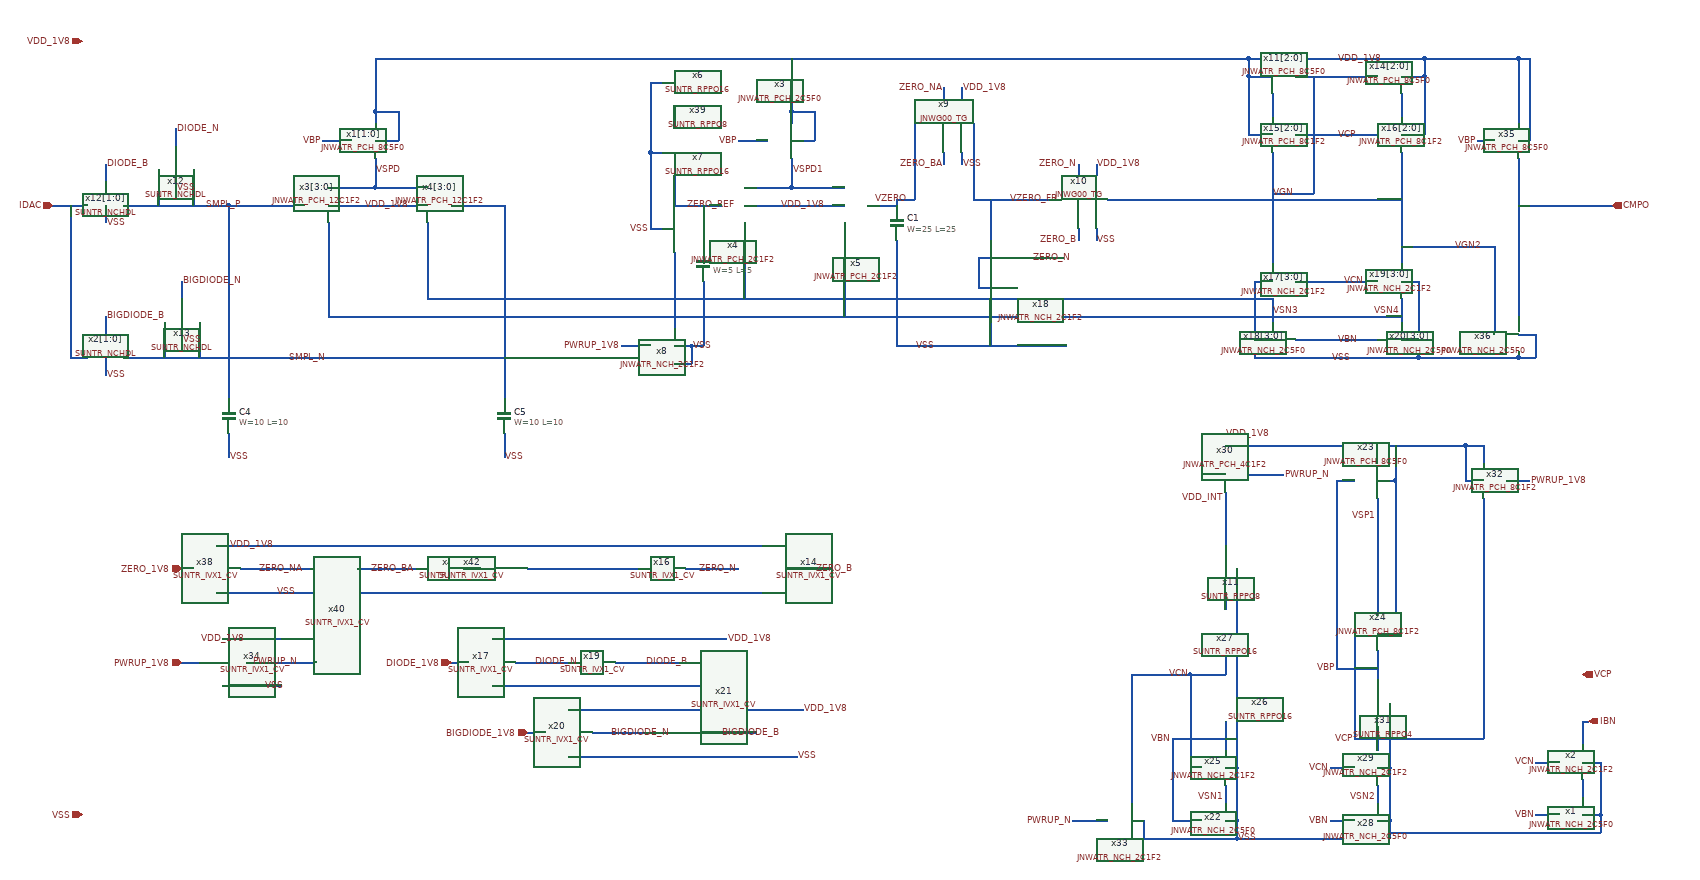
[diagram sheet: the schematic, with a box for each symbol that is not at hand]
v {xschem version=3.4.5 file_version=1.2
}
G {}
K {}
V {}
S {}
E {}
N 2170 -1300 2210 -1300 {
lab=VDD_1V8}
N 2170 -1330 2170 -1300 {
lab=VDD_1V8}
N 2170 -1330 2210 -1330 {
lab=VDD_1V8}
N 2210 -1330 2430 -1330 {
lab=VDD_1V8}
N 2430 -1300 2470 -1300 {
lab=VDD_1V8}
N 2470 -1330 2470 -1300 {
lab=VDD_1V8}
N 2430 -1330 2470 -1330 {
lab=VDD_1V8}
N 2430 -1270 2430 -1230 {
lab=#net1}
N 2210 -1270 2210 -1230 {
lab=#net2}
N 2170 -1200 2210 -1200 {
lab=VDD_1V8}
N 2170 -1300 2170 -1200 {
lab=VDD_1V8}
N 2430 -1200 2470 -1200 {
lab=VDD_1V8}
N 2470 -1300 2470 -1200 {
lab=VDD_1V8}
N 2210 -920 2210 -880 {
lab=VSN3}
N 2180 -950 2210 -950 {
lab=VSS}
N 2180 -950 2180 -820 {
lab=VSS}
N 2180 -820 2210 -820 {
lab=VSS}
N 2180 -850 2210 -850 {
lab=VSS}
N 2430 -920 2430 -880 {
lab=VSN4}
N 2430 -950 2460 -950 {
lab=VSS}
N 2460 -950 2460 -820 {
lab=VSS}
N 2430 -820 2460 -820 {
lab=VSS}
N 2430 -850 2460 -850 {
lab=VSS}
N 2210 -1170 2210 -980 {
lab=VGN}
N 2210 -820 2430 -820 {
lab=VSS}
N 2250 -850 2290 -850 {
lab=VBN}
N 2250 -950 2390 -950 {
lab=VCN}
N 2250 -1200 2390 -1200 {
lab=VCP}
N 2250 -1300 2390 -1300 {
lab=VGN}
N 2130 -90 2130 -60 {
lab=VSN1}
N 2130 -30 2150 -30 {
lab=VSS}
N 2150 -30 2150 0 {
lab=VSS}
N 2130 0 2150 0 {
lab=VSS}
N 2150 -120 2150 -30 {
lab=VSS}
N 2130 -120 2150 -120 {
lab=VSS}
N 2130 -200 2130 -150 {
lab=VBN}
N 2040 -30 2090 -30 {
lab=VBN}
N 2040 -170 2040 -30 {
lab=VBN}
N 2040 -170 2130 -170 {
lab=VBN}
N 2070 -120 2090 -120 {
lab=VCN}
N 2070 -280 2070 -120 {
lab=VCN}
N 2070 -280 2130 -280 {
lab=VCN}
N 2150 -240 2150 -120 {
lab=VSS}
N 2150 -350 2150 -240 {
lab=VSS}
N 2130 -310 2130 -280 {
lab=VCN}
N 2090 -620 2130 -620 {
lab=VDD_1V8}
N 2090 -650 2090 -620 {
lab=VDD_1V8}
N 2090 -650 2130 -650 {
lab=VDD_1V8}
N 2130 -690 2130 -650 {
lab=VDD_1V8}
N 2170 -620 2230 -620 {
lab=PWRUP_N}
N 2390 -90 2390 -60 {
lab=VSN2}
N 2390 -120 2410 -120 {
lab=VSS}
N 2410 -120 2410 -30 {
lab=VSS}
N 2390 -30 2410 -30 {
lab=VSS}
N 2390 0 2410 0 {
lab=VSS}
N 2410 -30 2410 0 {
lab=VSS}
N 2310 -120 2350 -120 {
lab=VCN}
N 2310 -30 2350 -30 {
lab=VBN}
N 2410 -230 2410 -120 {
lab=VSS}
N 2390 -190 2390 -150 {
lab=VCP}
N 2390 -320 2390 -270 {
lab=VBP}
N 2390 -350 2420 -350 {
lab=VDD_1V8}
N 2420 -450 2420 -350 {
lab=VDD_1V8}
N 2390 -610 2420 -610 {
lab=VDD_1V8}
N 2420 -640 2420 -610 {
lab=VDD_1V8}
N 2390 -580 2390 -540 {
lab=VSP1}
N 2350 -350 2350 -170 {
lab=VCP}
N 2350 -170 2390 -170 {
lab=VCP}
N 2320 -290 2390 -290 {
lab=VBP}
N 2320 -450 2320 -290 {
lab=VBP}
N 2320 -610 2350 -610 {
lab=VBP}
N 2130 -670 2390 -670 {
lab=VDD_1V8}
N 2390 -670 2390 -640 {
lab=VDD_1V8}
N 2570 -430 2570 -170 {
lab=VCP}
N 2390 -170 2570 -170 {
lab=VCP}
N 2540 -610 2570 -610 {
lab=VDD_1V8}
N 2540 -670 2540 -610 {
lab=VDD_1V8}
N 2540 -670 2570 -670 {
lab=VDD_1V8}
N 2570 -670 2570 -640 {
lab=VDD_1V8}
N 2390 -670 2540 -670 {
lab=VDD_1V8}
N 2610 -610 2650 -610 {
lab=PWRUP_1V8}
N 1970 0 2130 0 {
lab=VSS}
N 1970 -30 1990 -30 {
lab=VSS}
N 1990 -30 1990 0 {
lab=VSS}
N 1970 -280 1970 -60 {
lab=VCN}
N 1970 -280 2070 -280 {
lab=VCN}
N 1870 -30 1930 -30 {
lab=PWRUP_N}
N 2150 0 2390 0 {
lab=VSS}
N 420 -340 520 -340 {
lab=VDD_1V8}
N 420 -260 520 -260 {
lab=VSS}
N 460 -300 480 -300 {
lab=PWRUP_N}
N 350 -300 380 -300 {
lab=PWRUP_1V8}
N 480 -300 580 -300 {
lab=PWRUP_N}
N 2290 -850 2390 -850 {
lab=VBN}
N 2420 -670 2420 -640 {
lab=VDD_1V8}
N 2420 -610 2420 -450 {
lab=VDD_1V8}
N 2390 -540 2390 -380 {
lab=VSP1}
N 2570 -580 2570 -430 {
lab=VCP}
N 2130 -420 2130 -390 {
lab=#net3}
N 2150 -460 2150 -350 {
lab=VSS}
N 2320 -610 2320 -450 {
lab=VBP}
N 2130 -510 2130 -500 {
lab=VDD_INT}
N 2130 -590 2130 -570 {
lab=VDD_INT}
N 2430 -1040 2430 -980 {
lab=VGN2}
N 2430 -1170 2430 -1120 {
lab=VGN2}
N 2630 -1330 2630 -1220 {
lab=VDD_1V8}
N 2470 -1330 2630 -1330 {
lab=VDD_1V8}
N 2630 -1190 2650 -1190 {
lab=VDD_1V8}
N 2650 -1330 2650 -1190 {
lab=VDD_1V8}
N 2630 -1330 2650 -1330 {
lab=VDD_1V8}
N 2630 -830 2630 -820 {
lab=VSS}
N 2460 -820 2630 -820 {
lab=VSS}
N 2630 -860 2660 -860 {
lab=VSS}
N 2660 -860 2660 -820 {
lab=VSS}
N 2630 -820 2660 -820 {
lab=VSS}
N 2630 -920 2630 -890 {
lab=CMPO}
N 2630 -1160 2630 -920 {
lab=CMPO}
N 2630 -1080 2790 -1080 {
lab=CMPO}
N 2560 -1190 2590 -1190 {
lab=VBP}
N 2590 -1010 2590 -860 {
lab=VGN2}
N 2430 -1010 2590 -1010 {
lab=VGN2}
N 2430 -1120 2430 -1040 {
lab=VGN2}
N 680 -1190 720 -1190 {
lab=VDD_1V8}
N 720 -1240 720 -1190 {
lab=VDD_1V8}
N 680 -1240 720 -1240 {
lab=VDD_1V8}
N 680 -1240 680 -1220 {
lab=VDD_1V8}
N 680 -1160 680 -1110 {
lab=VSPD}
N 600 -1110 680 -1110 {
lab=VSPD}
N 680 -1110 770 -1110 {
lab=VSPD}
N 600 -1080 770 -1080 {
lab=VDD_1V8}
N 720 -1330 2170 -1330 {
lab=VDD_1V8}
N 770 -1050 770 -920 {
lab=VSN3}
N 770 -920 2210 -920 {
lab=VSN3}
N 600 -1050 600 -890 {
lab=VSN4}
N 600 -890 2430 -890 {
lab=VSN4}
N 590 -1190 640 -1190 {
lab=VBP}
N 2130 -570 2130 -510 {
lab=VDD_INT}
N 680 -1330 680 -1240 {
lab=VDD_1V8}
N 680 -1330 720 -1330 {
lab=VDD_1V8}
N 2280 -1300 2280 -1100 {
lab=VGN}
N 2210 -1100 2280 -1100 {
lab=VGN}
N 2660 -130 2700 -130 {
lab=VCN}
N 2660 -40 2700 -40 {
lab=VBN}
N 2410 -10 2740 -10 {
lab=VSS}
N 2740 -200 2750 -200 {
lab=IBN}
N 2740 -200 2740 -160 {
lab=IBN}
N 2740 -100 2740 -70 {
lab=#net4}
N 2740 -130 2770 -130 {
lab=VSS}
N 2770 -130 2770 -40 {
lab=VSS}
N 2740 -40 2770 -40 {
lab=VSS}
N 2740 -10 2770 -10 {
lab=VSS}
N 2770 -40 2770 -10 {
lab=VSS}
N 1150 -1040 1170 -1040 {
lab=VSS}
N 1150 -1170 1150 -1040 {
lab=VSS}
N 1190 -1000 1190 -870 {
lab=#net5}
N 1190 -840 1220 -840 {
lab=VSS}
N 1220 -840 1220 -810 {
lab=VSS}
N 1190 -810 1220 -810 {
lab=VSS}
N 1100 -840 1150 -840 {
lab=PWRUP_1V8}
N 1190 -1130 1190 -1080 {
lab=ZERO_REF}
N 1190 -1080 1270 -1080 {
lab=ZERO_REF}
N 1570 -1020 1570 -840 {
lab=VSS}
N 1240 -1080 1240 -1010 {
lab=ZERO_REF}
N 1240 -950 1240 -840 {
lab=VSS}
N 1220 -840 1240 -840 {
lab=VSS}
N 1520 -1080 1570 -1080 {
lab=VZERO}
N 1570 -1090 1570 -1080 {
lab=VZERO}
N 1570 -840 1670 -840 {
lab=VSS}
N 1700 -1090 1830 -1090 {
lab=VZERO_FB}
N 1670 -840 1860 -840 {
lab=VSS}
N 1730 -1090 1730 -1020 {
lab=VZERO_FB}
N 1730 -960 1730 -840 {
lab=VSS}
N 810 -1080 830 -1080 {
lab=SMPL_N}
N 520 -1080 540 -1080 {
lab=SMPL_P}
N 540 -1080 560 -1080 {
lab=SMPL_P}
N 410 -500 510 -500 {
lab=VDD_1V8}
N 410 -420 510 -420 {
lab=VSS}
N 450 -460 470 -460 {
lab=ZERO_NA}
N 470 -460 570 -460 {
lab=ZERO_NA}
N 350 -460 370 -460 {
lab=ZERO_1V8}
N 1390 -1190 1430 -1190 {
lab=VDD_1V8}
N 1430 -1240 1430 -1190 {
lab=VDD_1V8}
N 1390 -1240 1430 -1240 {
lab=VDD_1V8}
N 1390 -1240 1390 -1220 {
lab=VDD_1V8}
N 1390 -1160 1390 -1110 {
lab=VSPD1}
N 1310 -1110 1390 -1110 {
lab=VSPD1}
N 1390 -1110 1480 -1110 {
lab=VSPD1}
N 1310 -1080 1480 -1080 {
lab=VDD_1V8}
N 1300 -1190 1350 -1190 {
lab=VBP}
N 1390 -1330 1390 -1240 {
lab=VDD_1V8}
N 1150 -1290 1170 -1290 {
lab=VSS}
N 1150 -1290 1150 -1170 {
lab=VSS}
N 1190 -1250 1190 -1210 {
lab=#net6}
N 1150 -1170 1170 -1170 {
lab=VSS}
N 1770 -990 1800 -990 {
lab=ZERO_N}
N 510 -500 600 -500 {
lab=VDD_1V8}
N 510 -420 610 -420 {
lab=VSS}
N 1060 -460 1130 -460 {
lab=#net7}
N 1910 -1150 1910 -1130 {
lab=VDD_1V8}
N 1880 -1150 1880 -1130 {
lab=ZERO_N}
N 1880 -1040 1880 -1020 {
lab=ZERO_B}
N 1910 -1040 1910 -1020 {
lab=VSS}
N 1710 -990 1730 -990 {
lab=VSS}
N 1710 -990 1710 -940 {
lab=VSS}
N 1710 -940 1730 -940 {
lab=VSS}
N 1570 -1090 1600 -1090 {
lab=VZERO}
N 600 -500 610 -500 {
lab=VDD_1V8}
N 1930 -1090 2430 -1090 {
lab=VGN2}
N 1310 -1050 1310 -920 {
lab=VSN3}
N 1480 -1050 1480 -890 {
lab=VSN4}
N 1020 -420 1170 -420 {
lab=VSS}
N 1020 -500 1170 -500 {
lab=VDD_1V8}
N 1210 -460 1300 -460 {
lab=ZERO_N}
N 1170 -420 1340 -420 {
lab=VSS}
N 1180 -500 1340 -500 {
lab=VDD_1V8}
N 1380 -460 1460 -460 {
lab=ZERO_B}
N 1170 -500 1180 -500 {
lab=VDD_1V8}
N 900 -500 1020 -500 {
lab=VDD_1V8}
N 790 -500 900 -500 {
lab=VDD_1V8}
N 610 -500 790 -500 {
lab=VDD_1V8}
N 610 -420 790 -420 {
lab=VSS}
N 790 -420 900 -420 {
lab=VSS}
N 900 -420 1020 -420 {
lab=VSS}
N 950 -460 1060 -460 {
lab=#net7}
N 940 -460 950 -460 {
lab=#net7}
N 830 -460 860 -460 {
lab=#net8}
N 650 -460 750 -460 {
lab=ZERO_BA}
N 1680 -1280 1680 -1260 {
lab=VDD_1V8}
N 1650 -1280 1650 -1260 {
lab=ZERO_NA}
N 1650 -1170 1650 -1150 {
lab=ZERO_BA}
N 1680 -1170 1680 -1150 {
lab=VSS}
N 1600 -1220 1600 -1090 {
lab=VZERO}
N 1700 -1220 1700 -1090 {
lab=VZERO_FB}
N 430 -830 430 -750 {
lab=SMPL_P}
N 430 -690 430 -650 {
lab=VSS}
N 430 -1080 430 -830 {
lab=SMPL_P}
N 900 -830 900 -750 {
lab=SMPL_N}
N 900 -690 900 -650 {
lab=VSS}
N 900 -1080 900 -830 {
lab=SMPL_N}
N 830 -1080 900 -1080 {
lab=SMPL_N}
N 430 -1080 520 -1080 {
lab=SMPL_P}
N 280 -1080 430 -1080 {
lab=SMPL_P}
N 1240 -260 1270 -260 {
lab=VSS}
N 1240 -340 1280 -340 {
lab=VDD_1V8}
N 1140 -340 1240 -340 {
lab=VDD_1V8}
N 950 -340 1050 -340 {
lab=VDD_1V8}
N 1140 -260 1240 -260 {
lab=VSS}
N 950 -260 1050 -260 {
lab=VSS}
N 920 -300 940 -300 {
lab=DIODE_N}
N 1180 -300 1200 -300 {
lab=DIODE_B}
N 810 -300 840 -300 {
lab=DIODE_1V8}
N 880 -340 950 -340 {
lab=VDD_1V8}
N 880 -260 950 -260 {
lab=VSS}
N 940 -300 1010 -300 {
lab=DIODE_N}
N 1050 -340 1140 -340 {
lab=VDD_1V8}
N 1050 -260 1140 -260 {
lab=VSS}
N 1090 -300 1180 -300 {
lab=DIODE_B}
N 1370 -140 1400 -140 {
lab=VSS}
N 1370 -220 1410 -220 {
lab=VDD_1V8}
N 1270 -220 1370 -220 {
lab=VDD_1V8}
N 1080 -220 1180 -220 {
lab=VDD_1V8}
N 1270 -140 1370 -140 {
lab=VSS}
N 1080 -140 1180 -140 {
lab=VSS}
N 1050 -180 1070 -180 {
lab=BIGDIODE_N}
N 1310 -180 1330 -180 {
lab=BIGDIODE_B}
N 940 -180 970 -180 {
lab=BIGDIODE_1V8}
N 1010 -220 1080 -220 {
lab=VDD_1V8}
N 1010 -140 1080 -140 {
lab=VSS}
N 1070 -180 1140 -180 {
lab=BIGDIODE_N}
N 1180 -220 1270 -220 {
lab=VDD_1V8}
N 1180 -140 1270 -140 {
lab=VSS}
N 1220 -180 1310 -180 {
lab=BIGDIODE_B}
N 130 -1080 180 -1080 {
lab=IDAC}
N 280 -820 900 -820 {
lab=SMPL_N}
N 160 -1080 160 -820 {
lab=IDAC}
N 160 -820 180 -820 {
lab=IDAC}
N 180 -1080 190 -1080 {
lab=IDAC}
N 250 -1080 280 -1080 {
lab=SMPL_P}
N 220 -1080 220 -1050 {
lab=VSS}
N 220 -820 220 -790 {
lab=VSS}
N 250 -820 280 -820 {
lab=SMPL_N}
N 220 -1150 220 -1120 {
lab=DIODE_B}
N 220 -890 220 -860 {
lab=BIGDIODE_B}
N 340 -1140 340 -1110 {
lab=VSS}
N 310 -1140 310 -1080 {
lab=SMPL_P}
N 370 -1140 370 -1080 {
lab=SMPL_P}
N 340 -1210 340 -1180 {
lab=DIODE_N}
N 350 -880 350 -850 {
lab=VSS}
N 320 -880 320 -820 {
lab=SMPL_N}
N 380 -880 380 -820 {
lab=SMPL_N}
N 350 -950 350 -920 {
lab=DIODE_N}
N 180 -820 190 -820 {}
C {JNW_ATR_SKY130NM/JNWATR_PCH_8C5F0.sym} 2250 -1300 0 1 {name=x11[2:0]}
C {JNW_ATR_SKY130NM/JNWATR_PCH_8C5F0.sym} 2390 -1300 0 0 {name=x14[2:0]}
C {JNW_ATR_SKY130NM/JNWATR_PCH_8C1F2.sym} 2250 -1200 0 1 {name=x15[2:0]}
C {JNW_ATR_SKY130NM/JNWATR_PCH_8C1F2.sym} 2390 -1200 0 0 {name=x16[2:0]}
C {JNW_ATR_SKY130NM/JNWATR_NCH_2C1F2.sym} 2250 -950 0 1 {name=x17[3:0]}
C {JNW_ATR_SKY130NM/JNWATR_NCH_2C5F0.sym} 2250 -850 0 1 {name=x18[3:0]}
C {JNW_ATR_SKY130NM/JNWATR_NCH_2C1F2.sym} 2390 -950 0 0 {name=x19[3:0]}
C {JNW_ATR_SKY130NM/JNWATR_NCH_2C5F0.sym} 2390 -850 0 0 {name=x20[3:0]}
C {devices/lab_wire.sym} 2310 -820 0 1 {name=p9 sig_type=std_logic lab=VSS}
C {devices/lab_wire.sym} 2320 -1330 0 1 {name=p27 sig_type=std_logic lab=VDD_1V8}
C {devices/lab_wire.sym} 2330 -950 0 1 {name=p28 sig_type=std_logic lab=VCN}
C {devices/lab_wire.sym} 2320 -1200 0 1 {name=p29 sig_type=std_logic lab=VCP}
C {JNW_ATR_SKY130NM/JNWATR_NCH_2C5F0.sym} 2090 -30 0 0 {name=x22 }
C {JNW_ATR_SKY130NM/JNWATR_PCH_8C5F0.sym} 2350 -610 0 0 {name=x23 }
C {JNW_ATR_SKY130NM/JNWATR_PCH_8C1F2.sym} 2350 -350 0 0 {name=x24 }
C {JNW_ATR_SKY130NM/JNWATR_NCH_2C1F2.sym} 2090 -120 0 0 {name=x25 }
C {SUN_TR_SKY130NM/SUNTR_RPPO16.sym} 2130 -200 3 0 {name=x26 }
C {SUN_TR_SKY130NM/SUNTR_RPPO16.sym} 2130 -310 3 0 {name=x27 }
C {devices/lab_wire.sym} 2130 -690 0 1 {name=p33 sig_type=std_logic lab=VDD_1V8}
C {devices/lab_wire.sym} 2150 0 0 1 {name=p34 sig_type=std_logic lab=VSS}
C {JNW_ATR_SKY130NM/JNWATR_NCH_2C5F0.sym} 2350 -30 0 0 {name=x28 }
C {JNW_ATR_SKY130NM/JNWATR_NCH_2C1F2.sym} 2350 -120 0 0 {name=x29 }
C {JNW_ATR_SKY130NM/JNWATR_PCH_4C1F2.sym} 2170 -620 0 1 {name=x30 }
C {devices/lab_wire.sym} 2230 -620 0 1 {name=p35 sig_type=std_logic lab=PWRUP_N}
C {devices/lab_wire.sym} 2040 -170 0 0 {name=p36 sig_type=std_logic lab=VBN}
C {devices/lab_wire.sym} 2070 -280 0 0 {name=p37 sig_type=std_logic lab=VCN}
C {devices/lab_wire.sym} 2310 -120 0 0 {name=p38 sig_type=std_logic lab=VCN}
C {devices/lab_wire.sym} 2310 -30 0 0 {name=p39 sig_type=std_logic lab=VBN}
C {SUN_TR_SKY130NM/SUNTR_RPPO4.sym} 2390 -190 3 0 {name=x31 }
C {devices/lab_wire.sym} 2350 -170 0 0 {name=p40 sig_type=std_logic lab=VCP}
C {devices/lab_wire.sym} 2320 -290 0 0 {name=p41 sig_type=std_logic lab=VBP}
C {JNW_ATR_SKY130NM/JNWATR_PCH_8C1F2.sym} 2610 -610 0 1 {name=x32 }
C {devices/lab_wire.sym} 2650 -610 0 1 {name=p42 sig_type=std_logic lab=PWRUP_1V8}
C {JNW_ATR_SKY130NM/JNWATR_NCH_2C1F2.sym} 1930 -30 0 0 {name=x33 }
C {devices/lab_wire.sym} 1870 -30 0 0 {name=p43 sig_type=std_logic lab=PWRUP_N}
C {devices/ipin.sym} 180 -40 0 0 {name=p45 lab=VSS}
C {devices/ipin.sym} 350 -460 0 0 {name=p46 lab=ZERO_1V8}
C {devices/ipin.sym} 350 -300 0 0 {name=p47 lab=PWRUP_1V8}
C {SUN_TR_SKY130NM/SUNTR_IVX1_CV.sym} 380 -300 0 0 {name=x34 }
C {devices/lab_wire.sym} 460 -340 0 0 {name=p48 sig_type=std_logic lab=VDD_1V8}
C {devices/lab_wire.sym} 550 -300 0 0 {name=p49 sig_type=std_logic lab=PWRUP_N}
C {devices/lab_wire.sym} 490 -260 0 1 {name=p51 sig_type=std_logic lab=VSS}
C {devices/opin.sym} 2790 -1080 0 0 {name=p50 lab=CMPO
}
C {devices/ipin.sym} 180 -1360 0 0 {name=p44 lab=VDD_1V8}
C {devices/lab_wire.sym} 2130 -70 0 0 {name=p53 sig_type=std_logic lab=VSN1}
C {devices/lab_wire.sym} 2390 -70 0 0 {name=p54 sig_type=std_logic lab=VSN2}
C {devices/lab_wire.sym} 2390 -550 0 0 {name=p55 sig_type=std_logic lab=VSP1}
C {devices/lab_wire.sym} 2130 -580 0 0 {name=p57 sig_type=std_logic lab=VDD_INT}
C {devices/lab_wire.sym} 2210 -1100 0 1 {name=p60 sig_type=std_logic lab=VGN}
C {devices/lab_wire.sym} 2210 -900 0 1 {name=p61 sig_type=std_logic lab=VSN3}
C {devices/lab_wire.sym} 2430 -900 0 0 {name=p62 sig_type=std_logic lab=VSN4}
C {SUN_TR_SKY130NM/SUNTR_RPPO8.sym} 2130 -420 3 0 {name=x11 }
C {JNW_ATR_SKY130NM/JNWATR_PCH_8C5F0.sym} 2590 -1190 0 0 {name=x35 }
C {JNW_ATR_SKY130NM/JNWATR_NCH_2C5F0.sym} 2590 -860 0 0 {name=x36 }
C {devices/lab_wire.sym} 2520 -1010 0 1 {name=p64 sig_type=std_logic lab=VGN2}
C {devices/lab_wire.sym} 2560 -1190 0 0 {name=p63 sig_type=std_logic lab=VBP}
C {JNW_ATR_SKY130NM/JNWATR_PCH_12C1F2.sym} 560 -1080 0 0 {name=x3[3:0]}
C {JNW_ATR_SKY130NM/JNWATR_PCH_12C1F2.sym} 810 -1080 0 1 {name=x4[3:0]}
C {JNW_ATR_SKY130NM/JNWATR_PCH_8C5F0.sym} 640 -1190 0 0 {name=x1[1:0]}
C {devices/lab_wire.sym} 590 -1190 0 0 {name=p65 sig_type=std_logic lab=VBP}
C {devices/lab_wire.sym} 680 -1140 0 1 {name=p66 sig_type=std_logic lab=VSPD}
C {devices/lab_wire.sym} 2320 -850 0 1 {name=p31 sig_type=std_logic lab=VBN}
C {JNW_ATR_SKY130NM/JNWATR_NCH_2C5F0.sym} 2700 -40 0 0 {name=x1 }
C {JNW_ATR_SKY130NM/JNWATR_NCH_2C1F2.sym} 2700 -130 0 0 {name=x2 }
C {devices/lab_wire.sym} 2660 -130 0 0 {name=p1 sig_type=std_logic lab=VCN}
C {devices/lab_wire.sym} 2660 -40 0 0 {name=p2 sig_type=std_logic lab=VBN}
C {devices/opin.sym} 2750 -200 0 0 {name=p3 lab=IBN}
C {devices/opin.sym} 2740 -280 0 0 {name=p4 lab=VCP}
C {devices/lab_wire.sym} 660 -1080 0 1 {name=p15 sig_type=std_logic lab=VDD_1V8}
C {devices/lab_wire.sym} 1600 -840 0 1 {name=p6 sig_type=std_logic lab=VSS}
C {SUN_TR_SKY130NM/SUNTR_RPPO16.sym} 1190 -1330 1 0 {name=x6 }
C {SUN_TR_SKY130NM/SUNTR_RPPO16.sym} 1190 -1080 1 0 {name=x7 }
C {JNW_ATR_SKY130NM/JNWATR_NCH_2C1F2.sym} 1150 -840 0 0 {name=x8 }
C {devices/lab_wire.sym} 1100 -840 0 0 {name=p8 sig_type=std_logic lab=PWRUP_1V8}
C {devices/lab_wire.sym} 1220 -840 0 1 {name=p16 sig_type=std_logic lab=VSS}
C {devices/lab_wire.sym} 1150 -1040 0 0 {name=p17 sig_type=std_logic lab=VSS}
C {sky130_fd_pr/cap_mim_m3_1.sym} 1570 -1050 0 0 {name=C1 model=cap_mim_m3_1 W=25 L=25 MF=1 spiceprefix=X}
C {sky130_fd_pr/cap_mim_m3_1.sym} 1240 -980 0 0 {name=C2 model=cap_mim_m3_1 W=5 L=5 MF=1 spiceprefix=X}
C {JNW_ATR_SKY130NM/JNWATR_NCH_2C1F2.sym} 1770 -990 0 1 {name=x18 }
C {devices/lab_wire.sym} 1590 -1090 0 0 {name=p59 sig_type=std_logic lab=VZERO}
C {devices/lab_wire.sym} 1760 -1090 0 1 {name=p67 sig_type=std_logic lab=VZERO_FB}
C {SUN_TR_SKY130NM/SUNTR_IVX1_CV.sym} 370 -460 0 0 {name=x38 }
C {devices/lab_wire.sym} 510 -500 0 0 {name=p68 sig_type=std_logic lab=VDD_1V8}
C {devices/lab_wire.sym} 1300 -460 0 0 {name=p69 sig_type=std_logic lab=ZERO_N}
C {devices/lab_wire.sym} 510 -420 0 1 {name=p71 sig_type=std_logic lab=VSS}
C {devices/lab_wire.sym} 1210 -1080 0 1 {name=p70 sig_type=std_logic lab=ZERO_REF}
C {JNW_ATR_SKY130NM/JNWATR_PCH_2C1F2.sym} 1270 -1080 0 0 {name=x4}
C {JNW_ATR_SKY130NM/JNWATR_PCH_2C1F2.sym} 1520 -1080 0 1 {name=x5}
C {JNW_ATR_SKY130NM/JNWATR_PCH_2C5F0.sym} 1350 -1190 0 0 {name=x3}
C {devices/lab_wire.sym} 1300 -1190 0 0 {name=p5 sig_type=std_logic lab=VBP}
C {devices/lab_wire.sym} 1390 -1140 0 1 {name=p7 sig_type=std_logic lab=VSPD1}
C {devices/lab_wire.sym} 1370 -1080 0 1 {name=p72 sig_type=std_logic lab=VDD_1V8}
C {SUN_TR_SKY130NM/SUNTR_RPPO8.sym} 1190 -1210 1 0 {name=x39 }
C {devices/lab_wire.sym} 1800 -990 0 1 {name=p74 sig_type=std_logic lab=ZERO_N}
C {SUN_TR_SKY130NM/SUNTR_IVX1_CV.sym} 570 -460 0 0 {name=x40 }
C {devices/lab_wire.sym} 670 -460 0 1 {name=p75 sig_type=std_logic lab=ZERO_BA}
C {JNW_GR00_SKY130NM/JNWG00_TG.sym} 1820 -1090 0 0 {name=x10}
C {devices/lab_wire.sym} 1910 -1150 0 1 {name=p73 sig_type=std_logic lab=VDD_1V8}
C {devices/lab_wire.sym} 1910 -1020 0 1 {name=p80 sig_type=std_logic lab=VSS}
C {devices/lab_wire.sym} 1880 -1020 1 1 {name=p81 sig_type=std_logic lab=ZERO_B}
C {devices/lab_wire.sym} 1880 -1150 3 1 {name=p82 sig_type=std_logic lab=ZERO_N}
C {SUN_TR_SKY130NM/SUNTR_IVX1_CV.sym} 1130 -460 0 0 {name=x16 }
C {SUN_TR_SKY130NM/SUNTR_IVX1_CV.sym} 1300 -460 0 0 {name=x14 }
C {devices/lab_wire.sym} 1430 -460 0 1 {name=p85 sig_type=std_logic lab=ZERO_B}
C {SUN_TR_SKY130NM/SUNTR_IVX1_CV.sym} 750 -460 0 0 {name=x41 }
C {SUN_TR_SKY130NM/SUNTR_IVX1_CV.sym} 860 -460 0 0 {name=x42 }
C {JNW_GR00_SKY130NM/JNWG00_TG.sym} 1590 -1220 0 0 {name=x9}
C {devices/lab_wire.sym} 1680 -1280 0 1 {name=p22 sig_type=std_logic lab=VDD_1V8}
C {devices/lab_wire.sym} 1680 -1150 0 1 {name=p23 sig_type=std_logic lab=VSS}
C {devices/lab_wire.sym} 1650 -1150 1 1 {name=p24 sig_type=std_logic lab=ZERO_BA}
C {devices/lab_wire.sym} 1650 -1280 3 1 {name=p30 sig_type=std_logic lab=ZERO_NA}
C {devices/lab_wire.sym} 480 -460 0 1 {name=p76 sig_type=std_logic lab=ZERO_NA}
C {sky130_fd_pr/cap_mim_m3_1.sym} 430 -720 0 0 {name=C4 model=cap_mim_m3_1 W=10	 L=10 MF=1 spiceprefix=X}
C {devices/lab_wire.sym} 430 -650 0 1 {name=p18 sig_type=std_logic lab=VSS}
C {sky130_fd_pr/cap_mim_m3_1.sym} 900 -720 0 0 {name=C5 model=cap_mim_m3_1 W=10	 L=10 MF=1 spiceprefix=X}
C {devices/lab_wire.sym} 900 -650 0 1 {name=p19 sig_type=std_logic lab=VSS}
C {devices/ipin.sym} 810 -300 0 0 {name=p25 lab=DIODE_1V8}
C {SUN_TR_SKY130NM/SUNTR_IVX1_CV.sym} 840 -300 0 0 {name=x17 }
C {SUN_TR_SKY130NM/SUNTR_IVX1_CV.sym} 1010 -300 0 0 {name=x19 }
C {devices/lab_wire.sym} 1270 -260 0 1 {name=p26 sig_type=std_logic lab=VSS}
C {devices/lab_wire.sym} 1280 -340 0 1 {name=p32 sig_type=std_logic lab=VDD_1V8}
C {devices/lab_wire.sym} 950 -300 0 1 {name=p52 sig_type=std_logic lab=DIODE_N}
C {devices/lab_wire.sym} 1140 -300 0 1 {name=p56 sig_type=std_logic lab=DIODE_B}
C {devices/ipin.sym} 940 -180 0 0 {name=p58 lab=BIGDIODE_1V8}
C {SUN_TR_SKY130NM/SUNTR_IVX1_CV.sym} 970 -180 0 0 {name=x20 }
C {SUN_TR_SKY130NM/SUNTR_IVX1_CV.sym} 1140 -180 0 0 {name=x21 }
C {devices/lab_wire.sym} 1400 -140 0 1 {name=p77 sig_type=std_logic lab=VSS}
C {devices/lab_wire.sym} 1410 -220 0 1 {name=p78 sig_type=std_logic lab=VDD_1V8}
C {devices/lab_wire.sym} 1080 -180 0 1 {name=p79 sig_type=std_logic lab=BIGDIODE_N}
C {devices/lab_wire.sym} 1270 -180 0 1 {name=p83 sig_type=std_logic lab=BIGDIODE_B}
C {devices/ipin.sym} 130 -1080 0 0 {name=p86 lab=IDAC}
C {devices/lab_wire.sym} 390 -1080 0 1 {name=p10 sig_type=std_logic lab=SMPL_P}
C {devices/lab_wire.sym} 530 -820 0 1 {name=p11 sig_type=std_logic lab=SMPL_N}
C {SUN_TR_SKY130NM/SUNTR_NCHDL.sym} 220 -1120 1 0 {name=x12[1:0]}
C {devices/lab_wire.sym} 220 -1050 0 1 {name=p12 sig_type=std_logic lab=VSS}
C {SUN_TR_SKY130NM/SUNTR_NCHDL.sym} 220 -860 1 0 {name=x2[1:0]}
C {devices/lab_wire.sym} 220 -790 0 1 {name=p13 sig_type=std_logic lab=VSS}
C {devices/lab_wire.sym} 220 -1150 0 1 {name=p14 sig_type=std_logic lab=DIODE_B}
C {devices/lab_wire.sym} 220 -890 0 1 {name=p20 sig_type=std_logic lab=BIGDIODE_B}
C {SUN_TR_SKY130NM/SUNTR_NCHDL.sym} 340 -1180 1 0 {name=x12}
C {devices/lab_wire.sym} 340 -1110 0 1 {name=p21 sig_type=std_logic lab=VSS}
C {devices/lab_wire.sym} 340 -1210 0 1 {name=p84 sig_type=std_logic lab=DIODE_N}
C {SUN_TR_SKY130NM/SUNTR_NCHDL.sym} 350 -920 1 0 {name=x13}
C {devices/lab_wire.sym} 350 -850 0 1 {name=p87 sig_type=std_logic lab=VSS}
C {devices/lab_wire.sym} 350 -950 0 1 {name=p88 sig_type=std_logic lab=BIGDIODE_N}
